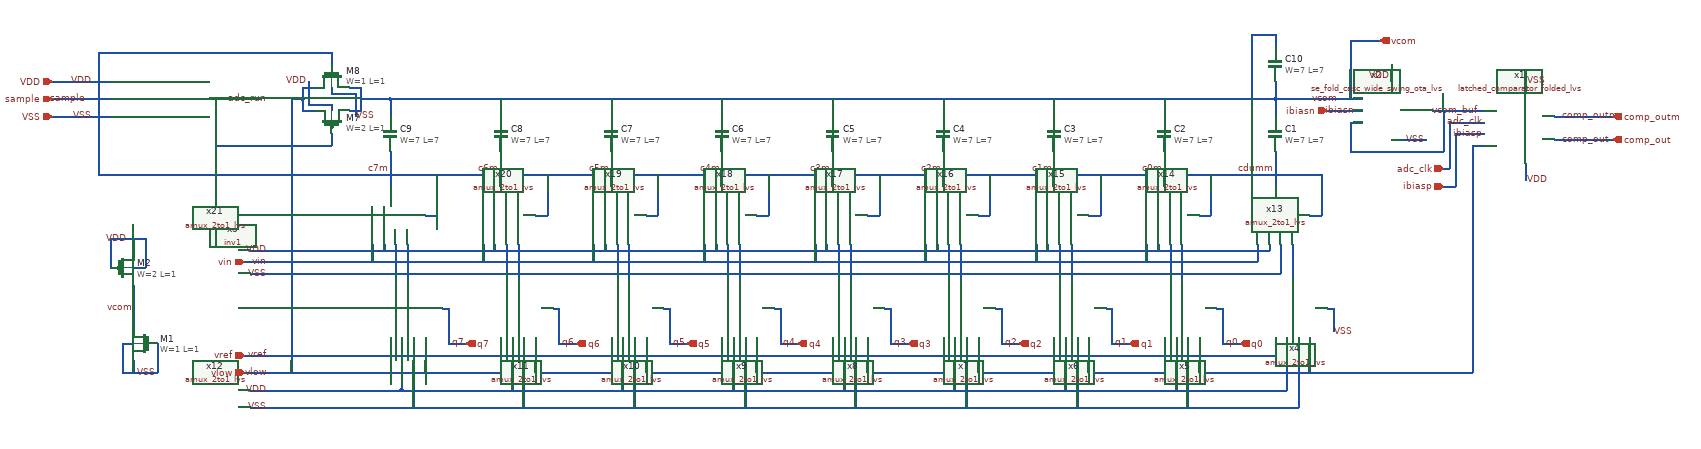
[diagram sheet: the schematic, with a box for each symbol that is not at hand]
v {xschem version=2.9.9 file_version=1.2 }
G {}
K {}
V {}
S {}
E {}
N 250 -790 250 -760 { lab=vcom}
N 250 -790 1770 -790 { lab=vcom}
N 1770 -790 1770 -760 { lab=vcom}
N 1580 -790 1580 -760 { lab=vcom}
N 1390 -790 1390 -760 { lab=vcom}
N 1200 -790 1200 -760 { lab=vcom}
N 1010 -790 1010 -760 { lab=vcom}
N 820 -790 820 -760 { lab=vcom}
N 630 -790 630 -760 { lab=vcom}
N 440 -790 440 -760 { lab=vcom}
N 1770 -790 1920 -790 { lab=vcom}
N 100 -810 100 -790 { lab=vlow}
N 100 -810 120 -810 { lab=vlow}
N 100 -790 100 -770 { lab=vlow}
N 100 -770 120 -770 { lab=vlow}
N 180 -810 200 -810 { lab=vcom}
N 200 -810 200 -770 { lab=vcom}
N 180 -770 200 -770 { lab=vcom}
N 150 -780 150 -770 { lab=VDD}
N 150 -810 150 -800 { lab=VSS}
N 200 -790 250 -790 { lab=vcom}
N 150 -800 190 -800 { lab=VSS}
N 190 -800 190 -760 { lab=VSS}
N 110 -820 110 -780 { lab=VDD}
N 110 -780 150 -780 { lab=VDD}
N 80 -790 100 -790 { lab=vlow}
N 2250 -720 2330 -720 { lab=comp_out}
N -330 -790 -230 -790 { lab=sample}
N -70 -790 30 -790 { lab=adc_run}
N -250 -790 -250 -660 { lab=sample}
N -250 -660 1850 -660 { lab=sample}
N 280 -540 280 -480 { lab=#net1}
N 470 -540 470 -480 { lab=#net2}
N 660 -540 660 -480 { lab=#net3}
N 850 -540 850 -480 { lab=#net4}
N 1040 -540 1040 -480 { lab=#net5}
N 1230 -540 1230 -480 { lab=#net6}
N 1420 -540 1420 -480 { lab=#net7}
N 1610 -540 1610 -480 { lab=#net8}
N 1800 -540 1800 -480 { lab=#net9}
N 10 -510 1740 -510 { lab=vin}
N 1740 -540 1740 -510 { lab=vin}
N 220 -540 220 -510 { lab=vin}
N 410 -540 410 -510 { lab=vin}
N 600 -540 600 -510 { lab=vin}
N 790 -540 790 -510 { lab=vin}
N 980 -540 980 -510 { lab=vin}
N 1170 -540 1170 -510 { lab=vin}
N 1360 -540 1360 -510 { lab=vin}
N 1550 -540 1550 -510 { lab=vin}
N 1770 -380 1770 -350 { lab=vref}
N 250 -380 250 -350 { lab=vref}
N 440 -380 440 -350 { lab=vref}
N 630 -380 630 -350 { lab=vref}
N 820 -380 820 -350 { lab=vref}
N 1010 -380 1010 -350 { lab=vref}
N 1200 -380 1200 -350 { lab=vref}
N 1390 -380 1390 -350 { lab=vref}
N 1580 -380 1580 -350 { lab=vref}
N 10 -350 1770 -350 { lab=vref}
N 1830 -380 1830 -320 { lab=vlow}
N 1640 -380 1640 -320 { lab=vlow}
N 1450 -380 1450 -320 { lab=vlow}
N 1260 -380 1260 -320 { lab=vlow}
N 1070 -380 1070 -320 { lab=vlow}
N 880 -380 880 -320 { lab=vlow}
N 690 -380 690 -320 { lab=vlow}
N 500 -380 500 -320 { lab=vlow}
N 310 -380 310 -320 { lab=vlow}
N 80 -790 80 -320 { lab=vlow}
N 250 -700 250 -640 { lab=c7m}
N 440 -700 440 -640 { lab=c6m}
N 630 -700 630 -640 { lab=c5m}
N 820 -700 820 -640 { lab=c4m}
N 1010 -700 1010 -640 { lab=c3m}
N 1200 -700 1200 -640 { lab=c2m}
N 1390 -700 1390 -640 { lab=c1m}
N 1580 -700 1580 -640 { lab=c0m}
N 1770 -700 1770 -640 { lab=cdumm}
N 310 -590 330 -590 { lab=sample}
N 330 -660 330 -590 { lab=sample}
N 500 -590 520 -590 { lab=sample}
N 520 -660 520 -590 { lab=sample}
N 690 -590 710 -590 { lab=sample}
N 710 -660 710 -590 { lab=sample}
N 880 -590 900 -590 { lab=sample}
N 900 -660 900 -590 { lab=sample}
N 1070 -590 1090 -590 { lab=sample}
N 1090 -660 1090 -590 { lab=sample}
N 1260 -590 1280 -590 { lab=sample}
N 1280 -660 1280 -590 { lab=sample}
N 1450 -590 1470 -590 { lab=sample}
N 1470 -660 1470 -590 { lab=sample}
N 1640 -590 1660 -590 { lab=sample}
N 1660 -660 1660 -590 { lab=sample}
N 1830 -590 1850 -590 { lab=sample}
N 1850 -660 1850 -590 { lab=sample}
N 350 -370 380 -370 { lab=q7}
N 540 -370 570 -370 { lab=q6}
N 730 -370 760 -370 { lab=q5}
N 920 -370 950 -370 { lab=q4}
N 1110 -370 1140 -370 { lab=q3}
N 1300 -370 1330 -370 { lab=q2}
N 1490 -370 1520 -370 { lab=q1}
N 1680 -370 1710 -370 { lab=q0}
N 340 -430 350 -430 { lab=q7}
N 350 -430 350 -370 { lab=q7}
N 530 -430 540 -430 { lab=q6}
N 540 -430 540 -370 { lab=q6}
N 720 -430 730 -430 { lab=q5}
N 730 -430 730 -370 { lab=q5}
N 910 -430 920 -430 { lab=q4}
N 920 -430 920 -370 { lab=q4}
N 1100 -430 1110 -430 { lab=q3}
N 1110 -430 1110 -370 { lab=q3}
N 1290 -430 1300 -430 { lab=q2}
N 1300 -430 1300 -370 { lab=q2}
N 1480 -430 1490 -430 { lab=q1}
N 1490 -430 1490 -370 { lab=q1}
N 1670 -430 1680 -430 { lab=q0}
N 1680 -430 1680 -370 { lab=q0}
N -250 -870 -250 -790 { lab=sample}
N -250 -870 150 -870 { lab=sample}
N 150 -870 150 -850 { lab=sample}
N -50 -790 -50 -710 { lab=adc_run}
N -50 -710 150 -710 { lab=adc_run}
N 150 -730 150 -710 { lab=adc_run}
N 1860 -430 1870 -430 { lab=VSS}
N 1870 -430 1870 -390 { lab=VSS}
N 2110 -710 2130 -710 { lab=vlow}
N 2080 -750 2130 -750 { lab=adc_clk}
N 2250 -760 2330 -760 { lab=comp_outm}
N 1900 -750 1920 -750 { lab=vcom_buf}
N 1900 -750 1900 -700 { lab=vcom_buf}
N 2040 -770 2130 -770 { lab=vcom_buf}
N 1900 -700 2060 -700 { lab=vcom_buf}
N 2060 -770 2060 -700 { lab=vcom_buf}
N 2110 -710 2110 -320 { lab=vlow}
N 10 -320 2110 -320 { lab=vlow}
N -290 -820 -230 -820 { lab=VDD}
N -290 -760 -230 -760 { lab=VSS}
N 1970 -850 1970 -820 { lab=VDD}
N 1970 -720 2030 -720 { lab=VSS}
N 1870 -770 1920 -770 { lab=ibiasn}
N 2200 -840 2200 -800 { lab=VSS}
N 2200 -680 2200 -650 { lab=VDD}
N 2080 -730 2130 -730 { lab=ibiasp}
N 270 -380 270 -290 { lab=VDD}
N 10 -290 270 -290 { lab=VDD}
N 270 -290 1790 -290 { lab=VDD}
N 1790 -380 1790 -290 { lab=VDD}
N 1810 -380 1810 -260 { lab=VSS}
N 10 -260 1810 -260 { lab=VSS}
N 460 -380 460 -290 { lab=VDD}
N 480 -380 480 -260 { lab=VSS}
N 290 -380 290 -260 { lab=VSS}
N 650 -380 650 -290 { lab=VDD}
N 840 -380 840 -290 { lab=VDD}
N 860 -380 860 -260 { lab=VSS}
N 670 -380 670 -260 { lab=VSS}
N 1030 -380 1030 -290 { lab=VDD}
N 1220 -380 1220 -290 { lab=VDD}
N 1240 -380 1240 -260 { lab=VSS}
N 1050 -380 1050 -260 { lab=VSS}
N 1410 -380 1410 -290 { lab=VDD}
N 1600 -380 1600 -290 { lab=VDD}
N 1620 -380 1620 -260 { lab=VSS}
N 1430 -380 1430 -260 { lab=VSS}
N 260 -540 260 -490 { lab=VSS}
N 450 -540 450 -490 { lab=VSS}
N 640 -540 640 -490 { lab=VSS}
N 830 -540 830 -490 { lab=VSS}
N 1020 -540 1020 -490 { lab=VSS}
N 1780 -540 1780 -490 { lab=VSS}
N 1590 -540 1590 -490 { lab=VSS}
N 1400 -540 1400 -490 { lab=VSS}
N 1210 -540 1210 -490 { lab=VSS}
N 10 -490 1780 -490 { lab=VSS}
N 240 -540 240 -530 { lab=VDD}
N 430 -540 430 -530 { lab=VDD}
N 620 -540 620 -530 { lab=VDD}
N 810 -540 810 -530 { lab=VDD}
N 1000 -540 1000 -530 { lab=VDD}
N 1760 -540 1760 -530 { lab=VDD}
N 1570 -540 1570 -530 { lab=VDD}
N 1380 -540 1380 -530 { lab=VDD}
N 1190 -540 1190 -530 { lab=VDD}
N 10 -530 1760 -530 { lab=VDD}
N 1770 -820 1770 -790 { lab=vcom}
N 1770 -900 1770 -880 { lab=vcom}
N 1730 -900 1770 -900 { lab=vcom}
N 1730 -900 1730 -790 { lab=vcom}
N -190 -470 -190 -400 { lab=vcom}
N -190 -500 -170 -500 { lab=VDD}
N -170 -550 -170 -500 { lab=VDD}
N -190 -550 -190 -530 { lab=VDD}
N -230 -550 -230 -500 { lab=VDD}
N -230 -550 -170 -550 { lab=VDD}
N -210 -370 -190 -370 { lab=VSS}
N -210 -370 -210 -320 { lab=VSS}
N -190 -340 -190 -320 { lab=VSS}
N -150 -370 -150 -320 { lab=VSS}
N -210 -320 -150 -320 { lab=VSS}
N -330 -820 -290 -820 { lab=VDD}
N -330 -760 -290 -760 { lab=VSS}
N 0 -320 10 -320 { lab=vlow}
N 0 -350 10 -350 { lab=vref}
N 0 -510 10 -510 { lab=vin}
N 1860 -770 1870 -770 { lab=ibiasn}
N 2080 -730 2080 -670 { lab=ibiasp}
N 2060 -640 2080 -640 { lab=ibiasp}
N 2070 -750 2080 -750 { lab=adc_clk}
N 2070 -750 2070 -680 { lab=adc_clk}
N 2080 -670 2080 -640 { lab=ibiasp}
N 2070 -680 2070 -670 { lab=adc_clk}
N 2060 -670 2070 -670 { lab=adc_clk}
N 2330 -720 2350 -720 { lab=comp_out}
N 2330 -760 2350 -760 { lab=comp_outm}
N 1900 -890 1900 -790 { lab=vcom}
N 1900 -890 1950 -890 { lab=vcom}
C {devices/title.sym} 160 -30 0 0 {name=l1 author="Nikhil Poole"}
C {sky130_fd_pr/pfet_01v8_hvt.sym} 150 -750 3 0 {name=M7
L=1
W=2
nf=1
mult=4
ad="'int((nf+1)/2) * W/nf * 0.29'" 
pd="'2*int((nf+1)/2) * (W/nf + 0.29)'"
as="'int((nf+2)/2) * W/nf * 0.29'" 
ps="'2*int((nf+2)/2) * (W/nf + 0.29)'"
nrd="'0.29 / W'" nrs="'0.29 / W'"
sa=0 sb=0 sd=0
model=pfet_01v8_hvt
spiceprefix=X
}
C {sky130_fd_pr/nfet_01v8.sym} 150 -830 3 1 {name=M8
L=1
W=1
nf=1 
mult=4
ad="'int((nf+1)/2) * W/nf * 0.29'" 
pd="'2*int((nf+1)/2) * (W/nf + 0.29)'"
as="'int((nf+2)/2) * W/nf * 0.29'" 
ps="'2*int((nf+2)/2) * (W/nf + 0.29)'"
nrd="'0.29 / W'" nrs="'0.29 / W'"
sa=0 sb=0 sd=0
model=nfet_01v8
spiceprefix=X
}
C {devices/lab_wire.sym} -30 -790 0 1 {name=l123 sig_type=std_logic lab=adc_run}
C {devices/lab_wire.sym} 2260 -720 0 1 {name=l124 sig_type=std_logic lab=comp_out}
C {devices/lab_wire.sym} -270 -790 0 0 {name=l125 sig_type=std_logic lab=sample}
C {devices/lab_wire.sym} 40 -510 0 0 {name=l7 sig_type=std_logic lab=vin}
C {devices/lab_wire.sym} 40 -350 0 0 {name=l39 sig_type=std_logic lab=vref}
C {devices/lab_wire.sym} 40 -320 0 0 {name=l40 sig_type=std_logic lab=vlow}
C {devices/lab_wire.sym} 380 -370 0 0 {name=l41 sig_type=std_logic lab=q7}
C {devices/lab_wire.sym} 570 -370 0 0 {name=l42 sig_type=std_logic lab=q6}
C {devices/lab_wire.sym} 760 -370 0 0 {name=l43 sig_type=std_logic lab=q5}
C {devices/lab_wire.sym} 950 -370 0 0 {name=l44 sig_type=std_logic lab=q4}
C {devices/lab_wire.sym} 1140 -370 0 0 {name=l45 sig_type=std_logic lab=q3}
C {devices/lab_wire.sym} 1330 -370 0 0 {name=l46 sig_type=std_logic lab=q2}
C {devices/lab_wire.sym} 1520 -370 0 0 {name=l47 sig_type=std_logic lab=q1}
C {devices/lab_wire.sym} 1710 -370 0 0 {name=l48 sig_type=std_logic lab=q0}
C {devices/lab_wire.sym} 250 -670 0 0 {name=l5 sig_type=std_logic lab=c7m}
C {devices/lab_wire.sym} 440 -670 0 0 {name=l8 sig_type=std_logic lab=c6m}
C {devices/lab_wire.sym} 630 -670 0 0 {name=l10 sig_type=std_logic lab=c5m}
C {devices/lab_wire.sym} 820 -670 0 0 {name=l12 sig_type=std_logic lab=c4m}
C {devices/lab_wire.sym} 1010 -670 0 0 {name=l13 sig_type=std_logic lab=c3m}
C {devices/lab_wire.sym} 1200 -670 0 0 {name=l16 sig_type=std_logic lab=c2m}
C {devices/lab_wire.sym} 1390 -670 0 0 {name=l19 sig_type=std_logic lab=c1m}
C {devices/lab_wire.sym} 1580 -670 0 0 {name=l22 sig_type=std_logic lab=c0m}
C {devices/lab_wire.sym} 1770 -670 0 0 {name=l25 sig_type=std_logic lab=cdumm}
C {devices/lab_wire.sym} 1880 -790 0 0 {name=l26 sig_type=std_logic lab=vcom}
C {devices/lab_wire.sym} 2130 -750 0 0 {name=l4 sig_type=std_logic lab=adc_clk}
C {devices/lab_wire.sym} 2260 -760 0 1 {name=l6 sig_type=std_logic lab=comp_outm}
C {devices/lab_wire.sym} 2120 -770 0 0 {name=l3 sig_type=std_logic lab=vcom_buf}
C {/home/users/nhpoole/ee272b/ee272b_mixed_signal_mmwave_accelerator/designs/inv1.sym} -180 -790 0 0 {name=x3}
C {devices/lab_wire.sym} 110 -820 0 0 {name=l9 sig_type=std_logic lab=VDD}
C {devices/lab_wire.sym} -260 -820 0 0 {name=l11 sig_type=std_logic lab=VDD}
C {devices/lab_wire.sym} -260 -760 0 0 {name=l14 sig_type=std_logic lab=VSS}
C {devices/lab_wire.sym} 190 -760 2 0 {name=l15 sig_type=std_logic lab=VSS}
C {/home/users/nhpoole/ee272b/ee272b_mixed_signal_mmwave_accelerator/designs/se_fold_casc_wide_swing_ota_lvs.sym} 1970 -770 0 0 {name=x2}
C {devices/lab_wire.sym} 1970 -830 0 0 {name=l17 sig_type=std_logic lab=VDD}
C {devices/lab_wire.sym} 2030 -720 0 0 {name=l18 sig_type=std_logic lab=VSS}
C {devices/lab_wire.sym} 1910 -770 0 0 {name=l20 sig_type=std_logic lab=ibiasn}
C {/home/users/nhpoole/ee272b/ee272b_mixed_signal_mmwave_accelerator/designs/latched_comparator_folded_lvs.sym} 2190 -740 2 1 {name=x1}
C {devices/lab_wire.sym} 2200 -650 0 1 {name=l21 sig_type=std_logic lab=VDD}
C {devices/lab_wire.sym} 2200 -820 0 1 {name=l23 sig_type=std_logic lab=VSS}
C {devices/lab_wire.sym} 2130 -730 0 0 {name=l24 sig_type=std_logic lab=ibiasp}
C {devices/lab_wire.sym} 1870 -390 0 1 {name=l2 sig_type=std_logic lab=VSS}
C {/home/users/nhpoole/ee272b/ee272b_mixed_signal_mmwave_accelerator/designs/amux_2to1_lvs.sym} 1800 -430 3 0 {name=x4}
C {/home/users/nhpoole/ee272b/ee272b_mixed_signal_mmwave_accelerator/designs/amux_2to1_lvs.sym} 1610 -430 3 0 {name=x5}
C {/home/users/nhpoole/ee272b/ee272b_mixed_signal_mmwave_accelerator/designs/amux_2to1_lvs.sym} 1420 -430 3 0 {name=x6}
C {/home/users/nhpoole/ee272b/ee272b_mixed_signal_mmwave_accelerator/designs/amux_2to1_lvs.sym} 1230 -430 3 0 {name=x7}
C {/home/users/nhpoole/ee272b/ee272b_mixed_signal_mmwave_accelerator/designs/amux_2to1_lvs.sym} 1040 -430 3 0 {name=x8}
C {/home/users/nhpoole/ee272b/ee272b_mixed_signal_mmwave_accelerator/designs/amux_2to1_lvs.sym} 850 -430 3 0 {name=x9}
C {/home/users/nhpoole/ee272b/ee272b_mixed_signal_mmwave_accelerator/designs/amux_2to1_lvs.sym} 660 -430 3 0 {name=x10}
C {/home/users/nhpoole/ee272b/ee272b_mixed_signal_mmwave_accelerator/designs/amux_2to1_lvs.sym} 470 -430 3 0 {name=x11}
C {/home/users/nhpoole/ee272b/ee272b_mixed_signal_mmwave_accelerator/designs/amux_2to1_lvs.sym} 280 -430 3 0 {name=x12}
C {devices/lab_wire.sym} 40 -290 0 0 {name=l27 sig_type=std_logic lab=VDD}
C {devices/lab_wire.sym} 40 -260 0 0 {name=l28 sig_type=std_logic lab=VSS}
C {/home/users/nhpoole/ee272b/ee272b_mixed_signal_mmwave_accelerator/designs/amux_2to1_lvs.sym} 1770 -590 3 0 {name=x13}
C {/home/users/nhpoole/ee272b/ee272b_mixed_signal_mmwave_accelerator/designs/amux_2to1_lvs.sym} 1580 -590 3 0 {name=x14}
C {/home/users/nhpoole/ee272b/ee272b_mixed_signal_mmwave_accelerator/designs/amux_2to1_lvs.sym} 1390 -590 3 0 {name=x15}
C {/home/users/nhpoole/ee272b/ee272b_mixed_signal_mmwave_accelerator/designs/amux_2to1_lvs.sym} 1200 -590 3 0 {name=x16}
C {/home/users/nhpoole/ee272b/ee272b_mixed_signal_mmwave_accelerator/designs/amux_2to1_lvs.sym} 1010 -590 3 0 {name=x17}
C {/home/users/nhpoole/ee272b/ee272b_mixed_signal_mmwave_accelerator/designs/amux_2to1_lvs.sym} 820 -590 3 0 {name=x18}
C {/home/users/nhpoole/ee272b/ee272b_mixed_signal_mmwave_accelerator/designs/amux_2to1_lvs.sym} 630 -590 3 0 {name=x19}
C {/home/users/nhpoole/ee272b/ee272b_mixed_signal_mmwave_accelerator/designs/amux_2to1_lvs.sym} 440 -590 3 0 {name=x20}
C {/home/users/nhpoole/ee272b/ee272b_mixed_signal_mmwave_accelerator/designs/amux_2to1_lvs.sym} 250 -590 3 0 {name=x21}
C {devices/lab_wire.sym} 40 -490 0 0 {name=l29 sig_type=std_logic lab=VSS}
C {devices/lab_wire.sym} 40 -530 0 0 {name=l30 sig_type=std_logic lab=VDD}
C {sky130_fd_pr/cap_mim_m3_1.sym} 1770 -730 0 0 {name=C1 model=cap_mim_m3_1 W=7 L=7 MF=1 spiceprefix=X}
C {sky130_fd_pr/cap_mim_m3_1.sym} 1580 -730 0 0 {name=C2 model=cap_mim_m3_1 W=7 L=7 MF=1 spiceprefix=X}
C {sky130_fd_pr/cap_mim_m3_1.sym} 1390 -730 0 0 {name=C3 model=cap_mim_m3_1 W=7 L=7 MF=2 spiceprefix=X}
C {sky130_fd_pr/cap_mim_m3_1.sym} 1200 -730 0 0 {name=C4 model=cap_mim_m3_1 W=7 L=7 MF=4 spiceprefix=X}
C {sky130_fd_pr/cap_mim_m3_1.sym} 1010 -730 0 0 {name=C5 model=cap_mim_m3_1 W=7 L=7 MF=8 spiceprefix=X}
C {sky130_fd_pr/cap_mim_m3_1.sym} 820 -730 0 0 {name=C6 model=cap_mim_m3_1 W=7 L=7 MF=16 spiceprefix=X}
C {sky130_fd_pr/cap_mim_m3_1.sym} 630 -730 0 0 {name=C7 model=cap_mim_m3_1 W=7 L=7 MF=32 spiceprefix=X}
C {sky130_fd_pr/cap_mim_m3_1.sym} 440 -730 0 0 {name=C8 model=cap_mim_m3_1 W=7 L=7 MF=64 spiceprefix=X}
C {sky130_fd_pr/cap_mim_m3_1.sym} 250 -730 0 0 {name=C9 model=cap_mim_m3_1 W=7 L=7 MF=128 spiceprefix=X}
C {sky130_fd_pr/cap_mim_m3_1.sym} 1770 -850 0 0 {name=C10 model=cap_mim_m3_1 W=7 L=7 MF=68 spiceprefix=X}
C {sky130_fd_pr/nfet_01v8.sym} -170 -370 0 1 {name=M1
L=1
W=1
nf=1 
mult=2
ad="'int((nf+1)/2) * W/nf * 0.29'" 
pd="'2*int((nf+1)/2) * (W/nf + 0.29)'"
as="'int((nf+2)/2) * W/nf * 0.29'" 
ps="'2*int((nf+2)/2) * (W/nf + 0.29)'"
nrd="'0.29 / W'" nrs="'0.29 / W'"
sa=0 sb=0 sd=0
model=nfet_01v8
spiceprefix=X
}
C {sky130_fd_pr/pfet_01v8_hvt.sym} -210 -500 2 1 {name=M2
L=1
W=2
nf=1
mult=2
ad="'int((nf+1)/2) * W/nf * 0.29'" 
pd="'2*int((nf+1)/2) * (W/nf + 0.29)'"
as="'int((nf+2)/2) * W/nf * 0.29'" 
ps="'2*int((nf+2)/2) * (W/nf + 0.29)'"
nrd="'0.29 / W'" nrs="'0.29 / W'"
sa=0 sb=0 sd=0
model=pfet_01v8_hvt
spiceprefix=X
}
C {devices/lab_wire.sym} -150 -320 0 0 {name=l31 sig_type=std_logic lab=VSS}
C {devices/lab_wire.sym} -200 -550 0 0 {name=l32 sig_type=std_logic lab=VDD}
C {devices/ipin.sym} -330 -790 0 0 {name=p1 lab=sample}
C {devices/ipin.sym} -330 -820 0 0 {name=p2 lab=VDD}
C {devices/ipin.sym} -330 -760 0 0 {name=p3 lab=VSS}
C {devices/ipin.sym} 0 -320 0 0 {name=p4 lab=vlow}
C {devices/ipin.sym} 0 -350 0 0 {name=p5 lab=vref}
C {devices/ipin.sym} 0 -510 0 0 {name=p6 lab=vin}
C {devices/ipin.sym} 380 -370 0 1 {name=p7 lab=q7}
C {devices/ipin.sym} 570 -370 0 1 {name=p8 lab=q6}
C {devices/ipin.sym} 760 -370 0 1 {name=p9 lab=q5}
C {devices/ipin.sym} 950 -370 0 1 {name=p10 lab=q4}
C {devices/ipin.sym} 1140 -370 0 1 {name=p11 lab=q3}
C {devices/ipin.sym} 1330 -370 0 1 {name=p12 lab=q2}
C {devices/ipin.sym} 1520 -370 0 1 {name=p13 lab=q1}
C {devices/ipin.sym} 1710 -370 0 1 {name=p14 lab=q0}
C {devices/ipin.sym} 1860 -770 0 0 {name=p15 lab=ibiasn}
C {devices/ipin.sym} 2060 -640 0 0 {name=p16 lab=ibiasp}
C {devices/ipin.sym} 2060 -670 0 0 {name=p17 lab=adc_clk}
C {devices/opin.sym} 2350 -720 0 0 {name=p18 lab=comp_out}
C {devices/opin.sym} 2350 -760 0 0 {name=p19 lab=comp_outm}
C {devices/lab_wire.sym} -190 -430 0 0 {name=l33 sig_type=std_logic lab=vcom}
C {devices/opin.sym} 1950 -890 0 0 {name=p20 lab=vcom}
